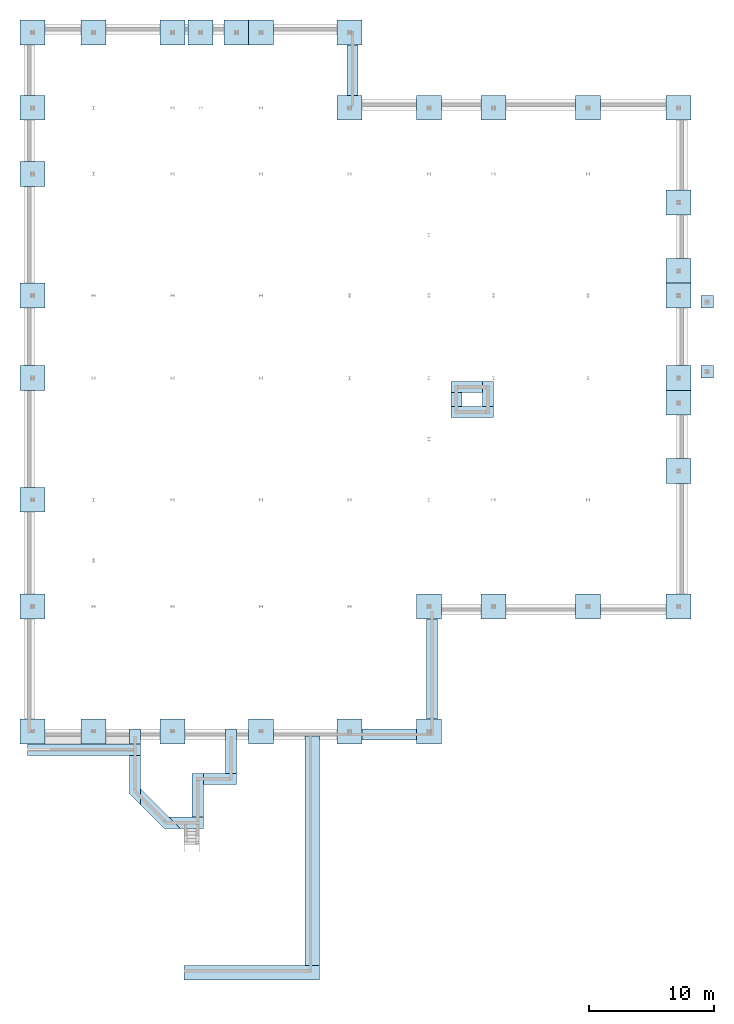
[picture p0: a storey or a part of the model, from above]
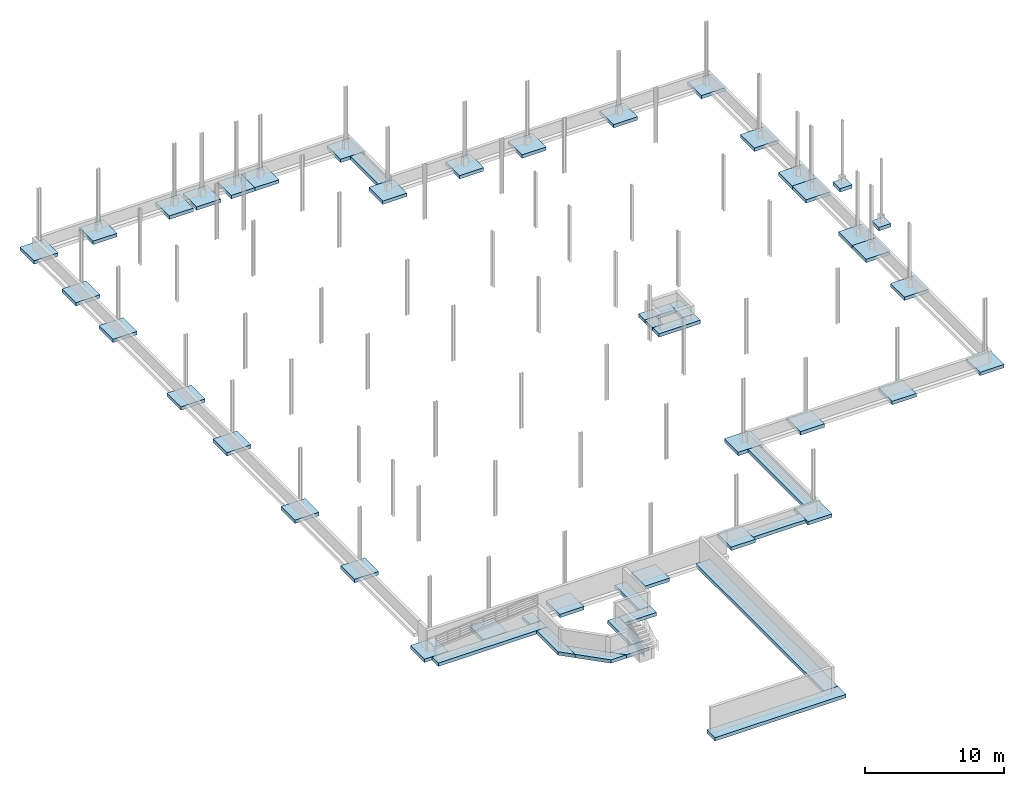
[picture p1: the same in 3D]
Properties of the parts of a building model (IFC2X3), part 1 of 3

# File
Description: ViewDefinition [CoordinationView]
File name: Project Number
Time: 2011-07-11T15:46:36
Written by: Autodesk Revit Architecture 2011 - 1.0
Made in: (Solibri IFC Optimizer)

# IfcProject, Project Number
Phase: Project Status

# IfcSite, Default
RefLatitude: 42, 21, 30, 344238; RefLongitude: -71, -3, -35, -194702; RefElevation: 0 m

# IfcBuilding
Pset_BuildingCommon - NumberOfStoreys: 4
PSet_Revit_Other - Project Issue Date: Issue Date; Project Status: Project Status; Client Name: Owner; Project Address: Enter address here; Project Name: Project Name; Project Number: Project Number; Category Description: OmniClass Table 11 Description; Category Code: OmniClass Table 11 Code

# IfcBuildingStorey (4)
PSet_Revit_Type_Graphics - Line Weight: 1; Color: 0; Line Pattern: Centre; Symbol: M_Level Head - Circle; Symbol at End 1 Default: no; Symbol at End 2 Default: yes
PSet_Revit_Type_Constraints - Elevation Base: 0
PSet_Revit_Type_Dimensions - Automatic Room Computation Height: yes
Name | Elevation (m) | Category Code | PSet_Revit_Constraints, Elevation (m) | Name
Roof - Main | 9.25 | Roof | 9.25 | Roof - Main
Second Floor | 4.57 | Floor | 4.57 | Second Floor
TOF Footing | -1 | Site | -1 | TOF Footing
First Floor | -3.5315e-13 | Floor | 0 | First Floor

# IfcBeam: M_K-Series Bar Joist-Rod Web:10K1:228953 (5)
In: First Floor
PSet_Revit_Structural Analysis - Start Release: 3; Start Fx: no; Start Fy: no; Start Fz: no; Start Mx: no; Start My: yes; Start Mz: yes; End Release: 1; End Fx: no; End Fy: no; End Fz: no; End Mx: yes; End My: yes; End Mz: yes; Analyze As: 1
PSet_Revit_Other - PanelArrayNum: 3; PanelArrayLength: 1.351 m; Panel: 0.450333 m; InstallationDate: InstallationDate; SerialNumber: SerialNumber; WarrantyStartDate: WarrantyStartDate; BarCode: BarCode; AssetIdentifier: AssetIdentifier; TagNumber: TagNumber
PSet_Revit_Analytical Model - Rigid Links: 0; Horizontal Projection: Default
PSet_Revit_Structural - Cut Length: 2.367 m; Structural Usage: 4
PSet_Revit_Construction - Start Offset: 0 m; Start Extension: 0 m; End Offset: 0 m; End Extension: 0 m
Pset_BeamCommon - Reference: M_K-Series Bar Joist-Rod Web:10K1; IsExternal: no; LoadBearing: yes; Span: 0.0095 m; Slope: 0 deg
PSet_Revit_Dimensions - Length: 2.367 m; Volume: 0.00307691 m3
PSet_Revit_Phasing - Phase Created: New Construction
PSet_Revit_Constraints - Work Plane: Level : Second Floor; Reference Level: Second Floor; Start Level Offset: 0 m; End Level Offset: 0 m; z-Direction Justification: 3; z-Direction Offset Value: -0.102 m; Lateral Justification: 0; Orientation: 0; Cross-Section Rotation: 0 deg
PSet_Revit_Type_Identity Data - Manufacturer: Manufacturer; OmniClass Number: 23.25.30.21.14.11; OmniClass Title: Metal Joists
PSet_Revit_Type_Dimensions - Web Thickness: 0.0095 m; Seat Length: 0.1 m; Seat Depth: 0.0635 m; Cord Leg: 0.032 m; Chord Thickness: 0.0065 m; Depth: 0.254 m
PSet_Revit_Type_Structural - M: 7.4
PSet_Revit_Type_Other - End Panel: 0.508 m; AccessibilityPerformance: AccessibilityPerformance; CodePerformance: CodePerformance; Color: Color; Constituents: Constituents; Features: Features; Finish: Finish; Grade: Grade; Material: Material; ModelReference: ModelReference; NominalHeight: NominalHeight; NominalLength: NominalLength; NominalWidth: NominalWidth; ProductionYear: ProductionYear; Reference: Reference; Shape: Shape; Size: Size; SustainabilityPerformance: SustainabilityPerformance; WarrantyDescription: WarrantyDescription; WarrantyDurationLabor: WarrantyDurationLabor; WarrantyDurationParts: WarrantyDurationParts; WarrantyGuarantorLabor: WarrantyGuarantorLabor; WarrantyGuarantorParts: WarrantyGuarantorParts; ExpectedLife: ExpectedLife; ReplacementCost: ReplacementCost; AssetAccountingType: FIXED; ModelLabel: ModelLabel
Name (M_K-Series Bar Joist-Rod Web:10K1:10K1:...)
228924
228926
228928
228920
228922

# IfcBeam: M_K-Series Bar Joist-Rod Web:14K1:175829 (456)
PSet_Revit_Constraints - Start Level Offset: 0 m; End Level Offset: 0 m; z-Direction Justification: 3; Lateral Justification: 0; Orientation: 0; Cross-Section Rotation: 0 deg
PSet_Revit_Structural Analysis - Start Release: 3; Start Fx: no; Start Fy: no; Start Fz: no; Start Mx: no; Start My: yes; Start Mz: yes; End Release: 1; End Fx: no; End Fy: no; End Fz: no; End Mx: yes; End My: yes; End Mz: yes; Analyze As: 1
PSet_Revit_Analytical Model - Rigid Links: 0; Horizontal Projection: Default
PSet_Revit_Structural - Structural Usage: 4
PSet_Revit_Construction - Start Offset: 0 m; Start Extension: 0 m; End Offset: 0 m; End Extension: 0 m
PSet_Revit_Phasing - Phase Created: New Construction
Pset_BeamCommon - Reference: M_K-Series Bar Joist-Rod Web:14K1; IsExternal: no; LoadBearing: yes; Span: 0.0095 m
PSet_Revit_Other - InstallationDate: InstallationDate; SerialNumber: SerialNumber; WarrantyStartDate: WarrantyStartDate; BarCode: BarCode; AssetIdentifier: AssetIdentifier; TagNumber: TagNumber
PSet_Revit_Type_Structural - M: 7.7
PSet_Revit_Type_Dimensions - Web Thickness: 0.0095 m; Seat Length: 0.1 m; Seat Depth: 0.0635 m; Cord Leg: 0.032 m; Chord Thickness: 0.0065 m; Depth: 0.356 m
PSet_Revit_Type_Identity Data - Manufacturer: Manufacturer; OmniClass Number: 23.25.30.21.14.11; OmniClass Title: Metal Joists
PSet_Revit_Type_Other - End Panel: 0.712 m; AccessibilityPerformance: AccessibilityPerformance; CodePerformance: CodePerformance; Color: Color; Constituents: Constituents; Features: Features; Finish: Finish; Grade: Grade; Material: Material; ModelReference: ModelReference; NominalHeight: NominalHeight; NominalLength: NominalLength; NominalWidth: NominalWidth; ProductionYear: ProductionYear; Reference: Reference; Shape: Shape; Size: Size; SustainabilityPerformance: SustainabilityPerformance; WarrantyDescription: WarrantyDescription; WarrantyDurationLabor: WarrantyDurationLabor; WarrantyDurationParts: WarrantyDurationParts; WarrantyGuarantorLabor: WarrantyGuarantorLabor; WarrantyGuarantorParts: WarrantyGuarantorParts; ExpectedLife: ExpectedLife; ReplacementCost: ReplacementCost; AssetAccountingType: FIXED; ModelLabel: ModelLabel
Name (M_K-Series Bar Joist-Rod Web:14K1:14K1:...) | In | Work Plane | Reference Level | z-Direction Offset Value (m) | Cut Length (m) = Length (m) | Slope (deg) | PanelArrayNum | PanelArrayLength (m) | Panel (m) | Volume (m3)
220116 | Second Floor | Level : Roof - Main | Roof - Main | 0 | 8.969 | 0 | 11 | 7.545 | 0.685909 | 0.0126419
220117 | Second Floor | Level : Roof - Main | Roof - Main | 0 | 8.969 | 0 | 11 | 7.545 | 0.685909 | 0.0126419
225612 | First Floor | Level : Second Floor | Second Floor | -0.102 | 5.309 | 0 | 5 | 3.885 | 0.777 | 0.00717022
220100 | Second Floor | Level : Roof - Main | Roof - Main | 0 | 8.975 | 0 | 11 | 7.551 | 0.686455 | 0.0126509
220081 | Second Floor | Level : Roof - Main | Roof - Main | 0 | 8.975 | 1.30141e-30 | 11 | 7.551 | 0.686455 | 0.0126509
189399 | Second Floor | Level : Roof - Main | Roof - Main | 0 | 8.57 | 0 | 10 | 7.146 | 0.7146 | 0.0120454
225467 | First Floor | Level : Second Floor | Second Floor | -0.102 | 8.57 | 0 | 10 | 7.146 | 0.7146 | 0.0120454
189397 | Second Floor | Level : Roof - Main | Roof - Main | 0 | 8.57 | 0 | 10 | 7.146 | 0.7146 | 0.0120454
225611 | First Floor | Level : Second Floor | Second Floor | -0.102 | 5.309 | 0 | 5 | 3.885 | 0.777 | 0.00717022
185401 | First Floor | Level : Second Floor | Second Floor | -0.102 | 6.629 | 0 | 7 | 5.205 | 0.743571 | 0.00914362
185451 | First Floor | Level : Second Floor | Second Floor | -0.102 | 8.57 | 0 | 10 | 7.146 | 0.7146 | 0.0120454
220080 | Second Floor | Level : Roof - Main | Roof - Main | 0 | 8.975 | 1.30141e-30 | 11 | 7.551 | 0.686455 | 0.0126509
185266 | First Floor | Level : Second Floor | Second Floor | -0.102 | 6.05 | 0 | 6 | 4.626 | 0.771 | 0.00827801
185267 | First Floor | Level : Second Floor | Second Floor | -0.102 | 6.05 | 0 | 6 | 4.626 | 0.771 | 0.00827801
220027 | Second Floor | Level : Roof - Main | Roof - Main | 0 | 8.975 | 1.30141e-30 | 11 | 7.551 | 0.686455 | 0.0126509
189395 | Second Floor | Level : Roof - Main | Roof - Main | 0 | 8.57 | 0 | 10 | 7.146 | 0.7146 | 0.0120454
220118 | Second Floor | Level : Roof - Main | Roof - Main | 0 | 8.969 | 0 | 11 | 7.545 | 0.685909 | 0.0126419
189398 | Second Floor | Level : Roof - Main | Roof - Main | 0 | 8.57 | 0 | 10 | 7.146 | 0.7146 | 0.0120454
189623 | Second Floor | Level : Roof - Main | Roof - Main | 0 | 5.309 | 2.01996e-30 | 5 | 3.885 | 0.777 | 0.00717022
185555 | First Floor | Level : Second Floor | Second Floor | -0.102 | 8.57 | 0 | 10 | 7.146 | 0.7146 | 0.0120454
189620 | Second Floor | Level : Roof - Main | Roof - Main | 0 | 5.309 | 2.01996e-30 | 5 | 3.885 | 0.777 | 0.00717022
190259 | Second Floor | Level : Roof - Main | Roof - Main | 0 | 8.57 | 1.97385e-30 | 10 | 7.146 | 0.7146 | 0.0120454
220061 | Second Floor | Level : Roof - Main | Roof - Main | 0 | 8.975 | 0 | 11 | 7.551 | 0.686455 | 0.0126509
220060 | Second Floor | Level : Roof - Main | Roof - Main | 0 | 8.975 | 0 | 11 | 7.551 | 0.686455 | 0.0126509
225615 | First Floor | Level : Second Floor | Second Floor | -0.102 | 5.309 | 0 | 5 | 3.885 | 0.777 | 0.00717022
185400 | First Floor | Level : Second Floor | Second Floor | -0.102 | 6.629 | 0 | 7 | 5.205 | 0.743571 | 0.00914362
185287 | First Floor | Level : Second Floor | Second Floor | -0.102 | 9.77 | 0 | 12 | 8.346 | 0.6955 | 0.0138394
185450 | First Floor | Level : Second Floor | Second Floor | -0.102 | 8.57 | 0 | 10 | 7.146 | 0.7146 | 0.0120454
189973 | Second Floor | Level : Roof - Main | Roof - Main | 0 | 8.57 | 0 | 10 | 7.146 | 0.7146 | 0.0120454
220097 | Second Floor | Level : Roof - Main | Roof - Main | 0 | 8.975 | 0 | 11 | 7.551 | 0.686455 | 0.0126509
185556 | First Floor | Level : Second Floor | Second Floor | -0.102 | 8.57 | 0 | 10 | 7.146 | 0.7146 | 0.0120454
185269 | First Floor | Level : Second Floor | Second Floor | -0.102 | 6.05 | 0 | 6 | 4.626 | 0.771 | 0.00827801
185362 | First Floor | Level : Second Floor | Second Floor | -0.102 | 5.309 | 0 | 5 | 3.885 | 0.777 | 0.00717022
185557 | First Floor | Level : Second Floor | Second Floor | -0.102 | 8.57 | 0 | 10 | 7.146 | 0.7146 | 0.0120454
190260 | Second Floor | Level : Roof - Main | Roof - Main | 0 | 8.57 | 1.97385e-30 | 10 | 7.146 | 0.7146 | 0.0120454
185553 | First Floor | Level : Second Floor | Second Floor | -0.102 | 8.57 | 0 | 10 | 7.146 | 0.7146 | 0.0120454
231532 | Second Floor | Level : Roof - Main | Roof - Main | 0 | 8.975 | 0 | 11 | 7.551 | 0.686455 | 0.0126509
185558 | First Floor | Level : Second Floor | Second Floor | -0.102 | 8.57 | 0 | 10 | 7.146 | 0.7146 | 0.0120454
189657 | Second Floor | Level : Roof - Main | Roof - Main | 0 | 9.769 | 9.79552e-31 | 12 | 8.345 | 0.695417 | 0.0138379
220062 | Second Floor | Level : Roof - Main | Roof - Main | 0 | 8.975 | 0 | 11 | 7.551 | 0.686455 | 0.0126509
225471 | First Floor | Level : Second Floor | Second Floor | -0.102 | 8.57 | 0 | 10 | 7.146 | 0.7146 | 0.0120454
190262 | Second Floor | Level : Roof - Main | Roof - Main | 0 | 8.57 | 1.97385e-30 | 10 | 7.146 | 0.7146 | 0.0120454
185740 | First Floor | Level : Second Floor | Second Floor | -0.102 | 10.039 | 0 | 12 | 8.615 | 0.717917 | 0.0142416
185286 | First Floor | Level : Second Floor | Second Floor | -0.102 | 9.77 | 0 | 12 | 8.346 | 0.6955 | 0.0138394
185268 | First Floor | Level : Second Floor | Second Floor | -0.102 | 6.05 | 0 | 6 | 4.626 | 0.771 | 0.00827801
225613 | First Floor | Level : Second Floor | Second Floor | -0.102 | 5.309 | 0 | 5 | 3.885 | 0.777 | 0.00717022
220112 | Second Floor | Level : Roof - Main | Roof - Main | 0 | 8.969 | 0 | 11 | 7.545 | 0.685909 | 0.0126419
189396 | Second Floor | Level : Roof - Main | Roof - Main | 0 | 8.57 | 0 | 10 | 7.146 | 0.7146 | 0.0120454
225473 | First Floor | Level : Second Floor | Second Floor | -0.102 | 8.57 | 0 | 10 | 7.146 | 0.7146 | 0.0120454
189434 | Second Floor | Level : Roof - Main | Roof - Main | 0 | 8.57 | 0 | 10 | 7.146 | 0.7146 | 0.0120454
189433 | Second Floor | Level : Roof - Main | Roof - Main | 0 | 8.57 | 0 | 10 | 7.146 | 0.7146 | 0.0120454
189725 | Second Floor | Level : Roof - Main | Roof - Main | 0 | 5.309 | 2.01996e-30 | 5 | 3.885 | 0.777 | 0.00717022
190338 | Second Floor | Level : Roof - Main | Roof - Main | 0 | 5.31 | 1.01005e-30 | 5 | 3.886 | 0.7772 | 0.00717171
220098 | Second Floor | Level : Roof - Main | Roof - Main | 0 | 8.975 | 0 | 11 | 7.551 | 0.686455 | 0.0126509
189970 | Second Floor | Level : Roof - Main | Roof - Main | 0 | 8.57 | 0 | 10 | 7.146 | 0.7146 | 0.0120454
231536 | Second Floor | Level : Roof - Main | Roof - Main | 0 | 8.975 | 0 | 11 | 7.551 | 0.686455 | 0.0126509
185492 | First Floor | Level : Second Floor | Second Floor | -0.102 | 10.039 | 0 | 12 | 8.615 | 0.717917 | 0.0142416
189464 | Second Floor | Level : Roof - Main | Roof - Main | 0 | 8.57 | 0 | 10 | 7.146 | 0.7146 | 0.0120454
220101 | Second Floor | Level : Roof - Main | Roof - Main | 0 | 8.975 | 0 | 11 | 7.551 | 0.686455 | 0.0126509
220114 | Second Floor | Level : Roof - Main | Roof - Main | 0 | 8.969 | 0 | 11 | 7.545 | 0.685909 | 0.0126419
189400 | Second Floor | Level : Roof - Main | Roof - Main | 0 | 8.57 | 0 | 10 | 7.146 | 0.7146 | 0.0120454
225616 | First Floor | Level : Second Floor | Second Floor | -0.102 | 5.309 | 0 | 5 | 3.885 | 0.777 | 0.00717022
220063 | Second Floor | Level : Roof - Main | Roof - Main | 0 | 8.975 | 0 | 11 | 7.551 | 0.686455 | 0.0126509
189411 | Second Floor | Level : Roof - Main | Roof - Main | 0 | 8.57 | 1.97385e-30 | 10 | 7.146 | 0.7146 | 0.0120454
189429 | Second Floor | Level : Roof - Main | Roof - Main | 0 | 8.57 | 0 | 10 | 7.146 | 0.7146 | 0.0120454
189968 | Second Floor | Level : Roof - Main | Roof - Main | 0 | 8.57 | 0 | 10 | 7.146 | 0.7146 | 0.0120454
220113 | Second Floor | Level : Roof - Main | Roof - Main | 0 | 8.969 | 0 | 11 | 7.545 | 0.685909 | 0.0126419
185399 | First Floor | Level : Second Floor | Second Floor | -0.102 | 6.629 | 0 | 7 | 5.205 | 0.743571 | 0.00914362
185437 | First Floor | Level : Second Floor | Second Floor | -0.102 | 9.77 | 0 | 12 | 8.346 | 0.6955 | 0.0138394
220045 | Second Floor | Level : Roof - Main | Roof - Main | 0 | 8.975 | 1.30141e-30 | 11 | 7.551 | 0.686455 | 0.0126509
189608 | Second Floor | Level : Roof - Main | Roof - Main | 0 | 5.309 | 0 | 5 | 3.885 | 0.777 | 0.00717022
185772 | First Floor | Level : Second Floor | Second Floor | -0.102 | 10.039 | 0 | 12 | 8.615 | 0.717917 | 0.0142416
189413 | Second Floor | Level : Roof - Main | Roof - Main | 0 | 8.57 | 1.97385e-30 | 10 | 7.146 | 0.7146 | 0.0120454
186278 | First Floor | Level : Second Floor | Second Floor | -0.102 | 6.629 | 0 | 7 | 5.205 | 0.743571 | 0.00914362
231535 | Second Floor | Level : Roof - Main | Roof - Main | 0 | 8.975 | 0 | 11 | 7.551 | 0.686455 | 0.0126509
185773 | First Floor | Level : Second Floor | Second Floor | -0.102 | 10.039 | 0 | 12 | 8.615 | 0.717917 | 0.0142416
189637 | Second Floor | Level : Roof - Main | Roof - Main | 0 | 5.309 | 0 | 5 | 3.885 | 0.777 | 0.00717022
220083 | Second Floor | Level : Roof - Main | Roof - Main | 0 | 8.975 | 1.30141e-30 | 11 | 7.551 | 0.686455 | 0.0126509
190339 | Second Floor | Level : Roof - Main | Roof - Main | 0 | 5.309 | 2.01996e-30 | 5 | 3.885 | 0.777 | 0.00717022
220025 | Second Floor | Level : Roof - Main | Roof - Main | 0 | 8.975 | 1.30141e-30 | 11 | 7.551 | 0.686455 | 0.0126509
220082 | Second Floor | Level : Roof - Main | Roof - Main | 0 | 8.975 | 1.30141e-30 | 11 | 7.551 | 0.686455 | 0.0126509
186277 | First Floor | Level : Second Floor | Second Floor | -0.102 | 6.629 | 0 | 7 | 5.205 | 0.743571 | 0.00914362
185538 | First Floor | Level : Second Floor | Second Floor | -0.102 | 10.039 | 0 | 12 | 8.615 | 0.717917 | 0.0142416
185491 | First Floor | Level : Second Floor | Second Floor | -0.102 | 10.039 | 0 | 12 | 8.615 | 0.717917 | 0.0142416
189853 | Second Floor | Level : Roof - Main | Roof - Main | 0 | 6.05 | 0 | 6 | 4.626 | 0.771 | 0.00827801
220028 | Second Floor | Level : Roof - Main | Roof - Main | 0 | 8.975 | 1.30141e-30 | 11 | 7.551 | 0.686455 | 0.0126509
189727 | Second Floor | Level : Roof - Main | Roof - Main | 0 | 5.309 | 2.01996e-30 | 5 | 3.885 | 0.777 | 0.00717022
220023 | Second Floor | Level : Roof - Main | Roof - Main | 0 | 8.975 | 1.30141e-30 | 11 | 7.551 | 0.686455 | 0.0126509
189707 | Second Floor | Level : Roof - Main | Roof - Main | 0 | 9.769 | 9.79552e-31 | 12 | 8.345 | 0.695417 | 0.0138379
185453 | First Floor | Level : Second Floor | Second Floor | -0.102 | 8.57 | 0 | 10 | 7.146 | 0.7146 | 0.0120454
185435 | First Floor | Level : Second Floor | Second Floor | -0.102 | 9.77 | 0 | 12 | 8.346 | 0.6955 | 0.0138394
225472 | First Floor | Level : Second Floor | Second Floor | -0.102 | 8.57 | 0 | 10 | 7.146 | 0.7146 | 0.0120454
225468 | First Floor | Level : Second Floor | Second Floor | -0.102 | 8.57 | 0 | 10 | 7.146 | 0.7146 | 0.0120454
185739 | First Floor | Level : Second Floor | Second Floor | -0.102 | 10.039 | 0 | 12 | 8.615 | 0.717917 | 0.0142416
190263 | Second Floor | Level : Roof - Main | Roof - Main | 0 | 8.57 | 1.97385e-30 | 10 | 7.146 | 0.7146 | 0.0120454
220099 | Second Floor | Level : Roof - Main | Roof - Main | 0 | 8.975 | 0 | 11 | 7.551 | 0.686455 | 0.0126509
231531 | Second Floor | Level : Roof - Main | Roof - Main | 0 | 8.975 | 0 | 11 | 7.551 | 0.686455 | 0.0126509
189622 | Second Floor | Level : Roof - Main | Roof - Main | 0 | 5.309 | 2.01996e-30 | 5 | 3.885 | 0.777 | 0.00717022
220022 | Second Floor | Level : Roof - Main | Roof - Main | 0 | 8.975 | 1.30141e-30 | 11 | 7.551 | 0.686455 | 0.0126509
186279 | First Floor | Level : Second Floor | Second Floor | -0.102 | 6.629 | 0 | 7 | 5.205 | 0.743571 | 0.00914362
225614 | First Floor | Level : Second Floor | Second Floor | -0.102 | 5.309 | 0 | 5 | 3.885 | 0.777 | 0.00717022
185534 | First Floor | Level : Second Floor | Second Floor | -0.102 | 10.039 | 0 | 12 | 8.615 | 0.717917 | 0.0142416
190336 | Second Floor | Level : Roof - Main | Roof - Main | 0 | 5.309 | 2.01996e-30 | 5 | 3.885 | 0.777 | 0.00717022
220043 | Second Floor | Level : Roof - Main | Roof - Main | 0 | 8.975 | 1.30141e-30 | 11 | 7.551 | 0.686455 | 0.0126509
220026 | Second Floor | Level : Roof - Main | Roof - Main | 0 | 8.975 | 1.30141e-30 | 11 | 7.551 | 0.686455 | 0.0126509
231533 | Second Floor | Level : Roof - Main | Roof - Main | 0 | 8.975 | 0 | 11 | 7.551 | 0.686455 | 0.0126509
188687 | First Floor | Level : Second Floor | Second Floor | -0.102 | 6.935 | 0 | 8 | 5.511 | 0.688875 | 0.00960109
220049 | Second Floor | Level : Roof - Main | Roof - Main | 0 | 8.975 | 1.30141e-30 | 11 | 7.551 | 0.686455 | 0.0126509
189415 | Second Floor | Level : Roof - Main | Roof - Main | 0 | 8.57 | 1.97385e-30 | 10 | 7.146 | 0.7146 | 0.0120454
185554 | First Floor | Level : Second Floor | Second Floor | -0.102 | 8.57 | 0 | 10 | 7.146 | 0.7146 | 0.0120454
186266 | First Floor | Level : Second Floor | Second Floor | -0.102 | 9.77 | 6.53056e-31 | 12 | 8.346 | 0.6955 | 0.0138394
220007 | Second Floor | Level : Roof - Main | Roof - Main | 0 | 8.975 | 0 | 11 | 7.551 | 0.686455 | 0.0126509
189331 | Second Floor | Level : Roof - Main | Roof - Main | 0 | 9.77 | 0 | 12 | 8.346 | 0.6955 | 0.0138394
189955 | Second Floor | Level : Roof - Main | Roof - Main | 0 | 8.57 | 1.97385e-30 | 10 | 7.146 | 0.7146 | 0.0120454
189969 | Second Floor | Level : Roof - Main | Roof - Main | 0 | 8.57 | 0 | 10 | 7.146 | 0.7146 | 0.0120454
185285 | First Floor | Level : Second Floor | Second Floor | -0.102 | 9.77 | 0 | 12 | 8.346 | 0.6955 | 0.0138394
189619 | Second Floor | Level : Roof - Main | Roof - Main | 0 | 5.309 | 2.01996e-30 | 5 | 3.885 | 0.777 | 0.00717022
220065 | Second Floor | Level : Roof - Main | Roof - Main | 0 | 8.975 | 0 | 11 | 7.551 | 0.686455 | 0.0126509
189956 | Second Floor | Level : Roof - Main | Roof - Main | 0 | 8.57 | 1.97385e-30 | 10 | 7.146 | 0.7146 | 0.0120454
185736 | First Floor | Level : Second Floor | Second Floor | -0.102 | 10.039 | 0 | 12 | 8.615 | 0.717917 | 0.0142416
225617 | First Floor | Level : Second Floor | Second Floor | -0.102 | 5.309 | 0 | 5 | 3.885 | 0.777 | 0.00717022
189462 | Second Floor | Level : Roof - Main | Roof - Main | 0 | 8.57 | 0 | 10 | 7.146 | 0.7146 | 0.0120454
185738 | First Floor | Level : Second Floor | Second Floor | -0.102 | 10.039 | 0 | 12 | 8.615 | 0.717917 | 0.0142416
189636 | Second Floor | Level : Roof - Main | Roof - Main | 0 | 5.309 | 0 | 5 | 3.885 | 0.777 | 0.00717022
185398 | First Floor | Level : Second Floor | Second Floor | -0.102 | 6.629 | 0 | 7 | 5.205 | 0.743571 | 0.00914362
189414 | Second Floor | Level : Roof - Main | Roof - Main | 0 | 8.57 | 1.97385e-30 | 10 | 7.146 | 0.7146 | 0.0120454
185769 | First Floor | Level : Second Floor | Second Floor | -0.102 | 10.039 | 0 | 12 | 8.615 | 0.717917 | 0.0142416
189671 | Second Floor | Level : Roof - Main | Roof - Main | 0 | 6.629 | 0 | 7 | 5.205 | 0.743571 | 0.00914362
225470 | First Floor | Level : Second Floor | Second Floor | -0.102 | 8.57 | 0 | 10 | 7.146 | 0.7146 | 0.0120454
186263 | First Floor | Level : Second Floor | Second Floor | -0.102 | 9.77 | 6.53056e-31 | 12 | 8.346 | 0.6955 | 0.0138394
189670 | Second Floor | Level : Roof - Main | Roof - Main | 0 | 6.629 | 0 | 7 | 5.205 | 0.743571 | 0.00914362
188689 | First Floor | Level : Second Floor | Second Floor | -0.102 | 6.935 | 0 | 8 | 5.511 | 0.688875 | 0.00960109
189639 | Second Floor | Level : Roof - Main | Roof - Main | 0 | 5.309 | 0 | 5 | 3.885 | 0.777 | 0.00717022
189972 | Second Floor | Level : Roof - Main | Roof - Main | 0 | 8.57 | 0 | 10 | 7.146 | 0.7146 | 0.0120454
189669 | Second Floor | Level : Roof - Main | Roof - Main | 0 | 6.629 | 0 | 7 | 5.205 | 0.743571 | 0.00914362
185288 | First Floor | Level : Second Floor | Second Floor | -0.102 | 9.77 | 0 | 12 | 8.346 | 0.6955 | 0.0138394
190337 | Second Floor | Level : Roof - Main | Roof - Main | 0 | 5.309 | 2.01996e-30 | 5 | 3.885 | 0.777 | 0.00717022
185668 | First Floor | Level : Second Floor | Second Floor | -0.102 | 8.57 | 0 | 10 | 7.146 | 0.7146 | 0.0120454
220024 | Second Floor | Level : Roof - Main | Roof - Main | 0 | 8.975 | 1.30141e-30 | 11 | 7.551 | 0.686455 | 0.0126509
189705 | Second Floor | Level : Roof - Main | Roof - Main | 0 | 9.769 | 9.79552e-31 | 12 | 8.345 | 0.695417 | 0.0138379
185774 | First Floor | Level : Second Floor | Second Floor | -0.102 | 10.039 | 0 | 12 | 8.615 | 0.717917 | 0.0142416
185490 | First Floor | Level : Second Floor | Second Floor | -0.102 | 10.039 | 0 | 12 | 8.615 | 0.717917 | 0.0142416
189640 | Second Floor | Level : Roof - Main | Roof - Main | 0 | 5.309 | 0 | 5 | 3.885 | 0.777 | 0.00717022
189854 | Second Floor | Level : Roof - Main | Roof - Main | 0 | 6.05 | 0 | 6 | 4.626 | 0.771 | 0.00827801
188688 | First Floor | Level : Second Floor | Second Floor | -0.102 | 6.935 | 0 | 8 | 5.511 | 0.688875 | 0.00960109
190261 | Second Floor | Level : Roof - Main | Roof - Main | 0 | 8.57 | 1.97385e-30 | 10 | 7.146 | 0.7146 | 0.0120454
185824 | First Floor | Level : Second Floor | Second Floor | -0.102 | 9.77 | 0 | 12 | 8.346 | 0.6955 | 0.0138394
231534 | Second Floor | Level : Roof - Main | Roof - Main | 0 | 8.975 | 0 | 11 | 7.551 | 0.686455 | 0.0126509
185735 | First Floor | Level : Second Floor | Second Floor | -0.102 | 10.039 | 0 | 12 | 8.615 | 0.717917 | 0.0142416
220047 | Second Floor | Level : Roof - Main | Roof - Main | 0 | 8.975 | 1.30141e-30 | 11 | 7.551 | 0.686455 | 0.0126509
185434 | First Floor | Level : Second Floor | Second Floor | -0.102 | 9.77 | 0 | 12 | 8.346 | 0.6955 | 0.0138394
185669 | First Floor | Level : Second Floor | Second Floor | -0.102 | 8.57 | 0 | 10 | 7.146 | 0.7146 | 0.0120454
189635 | Second Floor | Level : Roof - Main | Roof - Main | 0 | 5.309 | 0 | 5 | 3.885 | 0.777 | 0.00717022
220096 | Second Floor | Level : Roof - Main | Roof - Main | 0 | 8.975 | 0 | 11 | 7.551 | 0.686455 | 0.0126509
189668 | Second Floor | Level : Roof - Main | Roof - Main | 0 | 6.629 | 0 | 7 | 5.205 | 0.743571 | 0.00914362
220001 | Second Floor | Level : Roof - Main | Roof - Main | 0 | 8.975 | 0 | 11 | 7.551 | 0.686455 | 0.0126509
189306 | Second Floor | Level : Roof - Main | Roof - Main | 0 | 5.309 | 0 | 5 | 3.885 | 0.777 | 0.00717022
189431 | Second Floor | Level : Roof - Main | Roof - Main | 0 | 8.57 | 0 | 10 | 7.146 | 0.7146 | 0.0120454
188686 | First Floor | Level : Second Floor | Second Floor | -0.102 | 6.935 | 0 | 8 | 5.511 | 0.688875 | 0.00960109
189412 | Second Floor | Level : Roof - Main | Roof - Main | 0 | 8.57 | 1.97385e-30 | 10 | 7.146 | 0.7146 | 0.0120454
189724 | Second Floor | Level : Roof - Main | Roof - Main | 0 | 5.309 | 2.01996e-30 | 5 | 3.885 | 0.777 | 0.00717022
185539 | First Floor | Level : Second Floor | Second Floor | -0.102 | 10.039 | 0 | 12 | 8.615 | 0.717917 | 0.0142416
220066 | Second Floor | Level : Roof - Main | Roof - Main | 0 | 8.975 | 0 | 11 | 7.551 | 0.686455 | 0.0126509
189654 | Second Floor | Level : Roof - Main | Roof - Main | 0 | 9.769 | 9.79552e-31 | 12 | 8.345 | 0.695417 | 0.0138379
186281 | First Floor | Level : Second Floor | Second Floor | -0.102 | 6.629 | 0 | 7 | 5.205 | 0.743571 | 0.00914362
185752 | First Floor | Level : Second Floor | Second Floor | -0.102 | 10.039 | 0 | 12 | 8.615 | 0.717917 | 0.0142416
185756 | First Floor | Level : Second Floor | Second Floor | -0.102 | 10.039 | 0 | 12 | 8.615 | 0.717917 | 0.0142416
185632 | First Floor | Level : Second Floor | Second Floor | -0.102 | 9.77 | 0 | 12 | 8.346 | 0.6955 | 0.0138394
189428 | Second Floor | Level : Roof - Main | Roof - Main | 0 | 8.57 | 0 | 10 | 7.146 | 0.7146 | 0.0120454
219950 | Second Floor | Level : Roof - Main | Roof - Main | 0 | 8.975 | 0 | 11 | 7.551 | 0.686455 | 0.0126509
225469 | First Floor | Level : Second Floor | Second Floor | -0.102 | 8.57 | 0 | 10 | 7.146 | 0.7146 | 0.0120454
219990 | Second Floor | Level : Roof - Main | Roof - Main | 0 | 8.975 | 1.30141e-30 | 11 | 7.551 | 0.686455 | 0.0126509
189706 | Second Floor | Level : Roof - Main | Roof - Main | 0 | 9.769 | 9.79552e-31 | 12 | 8.345 | 0.695417 | 0.0138379
188723 | First Floor | Level : Second Floor | Second Floor | -0.102 | 2.834 | 0 | 2 | 1.41 | 0.705 | 0.00347009
185631 | First Floor | Level : Second Floor | Second Floor | -0.102 | 9.77 | 0 | 12 | 8.346 | 0.6955 | 0.0138394
185537 | First Floor | Level : Second Floor | Second Floor | -0.102 | 10.039 | 0 | 12 | 8.615 | 0.717917 | 0.0142416
189465 | Second Floor | Level : Roof - Main | Roof - Main | 0 | 8.57 | 0 | 10 | 7.146 | 0.7146 | 0.0120454
185535 | First Floor | Level : Second Floor | Second Floor | -0.102 | 10.039 | 0 | 12 | 8.615 | 0.717917 | 0.0142416
186299 | First Floor | Level : Second Floor | Second Floor | -0.102 | 9.77 | 0 | 12 | 8.346 | 0.6955 | 0.0138394
189730 | Second Floor | Level : Roof - Main | Roof - Main | 0 | 5.309 | 2.01996e-30 | 5 | 3.885 | 0.777 | 0.00717022
190335 | Second Floor | Level : Roof - Main | Roof - Main | 0 | 5.309 | 2.01996e-30 | 5 | 3.885 | 0.777 | 0.00717022
190341 | Second Floor | Level : Roof - Main | Roof - Main | 0 | 5.309 | 2.01996e-30 | 5 | 3.885 | 0.777 | 0.00717022
185617 | First Floor | Level : Second Floor | Second Floor | -0.102 | 6.05 | 0 | 6 | 4.626 | 0.771 | 0.00827801
189430 | Second Floor | Level : Roof - Main | Roof - Main | 0 | 8.57 | 0 | 10 | 7.146 | 0.7146 | 0.0120454
189417 | Second Floor | Level : Roof - Main | Roof - Main | 0 | 8.57 | 1.97385e-30 | 10 | 7.146 | 0.7146 | 0.0120454
189702 | Second Floor | Level : Roof - Main | Roof - Main | 0 | 9.769 | 9.79552e-31 | 12 | 8.345 | 0.695417 | 0.0138379
189621 | Second Floor | Level : Roof - Main | Roof - Main | 0 | 5.309 | 2.01996e-30 | 5 | 3.885 | 0.777 | 0.00717022
220079 | Second Floor | Level : Roof - Main | Roof - Main | 0 | 8.975 | 1.30141e-30 | 11 | 7.551 | 0.686455 | 0.0126509
189335 | Second Floor | Level : Roof - Main | Roof - Main | 0 | 9.769 | 0 | 12 | 8.345 | 0.695417 | 0.0138379
189652 | Second Floor | Level : Roof - Main | Roof - Main | 0 | 9.77 | 6.53056e-31 | 12 | 8.346 | 0.6955 | 0.0138394
188772 | First Floor | Level : Second Floor | Second Floor | -0.102 | 5.697 | 1.31467e-30 | 6 | 4.273 | 0.712167 | 0.00775028
185718 | First Floor | Level : Second Floor | Second Floor | -0.102 | 9.77 | 0 | 12 | 8.346 | 0.6955 | 0.0138394
190340 | Second Floor | Level : Roof - Main | Roof - Main | 0 | 5.309 | 2.01996e-30 | 5 | 3.885 | 0.777 | 0.00717022
189726 | Second Floor | Level : Roof - Main | Roof - Main | 0 | 5.309 | 2.01996e-30 | 5 | 3.885 | 0.777 | 0.00717022
185363 | First Floor | Level : Second Floor | Second Floor | -0.102 | 5.309 | 0 | 5 | 3.885 | 0.777 | 0.00717022
189690 | Second Floor | Level : Roof - Main | Roof - Main | 0 | 9.769 | 9.79552e-31 | 12 | 8.345 | 0.695417 | 0.0138379
185823 | First Floor | Level : Second Floor | Second Floor | -0.102 | 9.77 | 0 | 12 | 8.346 | 0.6955 | 0.0138394
189691 | Second Floor | Level : Roof - Main | Roof - Main | 0 | 9.769 | 9.79552e-31 | 12 | 8.345 | 0.695417 | 0.0138379
220115 | Second Floor | Level : Roof - Main | Roof - Main | 0 | 8.969 | 0 | 11 | 7.545 | 0.685909 | 0.0126419
189416 | Second Floor | Level : Roof - Main | Roof - Main | 0 | 8.57 | 1.97385e-30 | 10 | 7.146 | 0.7146 | 0.0120454
189586 | Second Floor | Level : Roof - Main | Roof - Main | 0 | 5.309 | 0 | 5 | 3.885 | 0.777 | 0.00717022
189463 | Second Floor | Level : Roof - Main | Roof - Main | 0 | 8.57 | 0 | 10 | 7.146 | 0.7146 | 0.0120454
189634 | Second Floor | Level : Roof - Main | Roof - Main | 0 | 5.309 | 0 | 5 | 3.885 | 0.777 | 0.00717022
186265 | First Floor | Level : Second Floor | Second Floor | -0.102 | 9.77 | 6.53056e-31 | 12 | 8.346 | 0.6955 | 0.0138394
189953 | Second Floor | Level : Roof - Main | Roof - Main | 0 | 8.57 | 1.97385e-30 | 10 | 7.146 | 0.7146 | 0.0120454
219946 | Second Floor | Level : Roof - Main | Roof - Main | 0 | 8.975 | 0 | 11 | 7.551 | 0.686455 | 0.0126509
189590 | Second Floor | Level : Roof - Main | Roof - Main | 0 | 5.309 | 0 | 5 | 3.885 | 0.777 | 0.00717022
220064 | Second Floor | Level : Roof - Main | Roof - Main | 0 | 8.975 | 0 | 11 | 7.551 | 0.686455 | 0.0126509
186298 | First Floor | Level : Second Floor | Second Floor | -0.102 | 9.77 | 0 | 12 | 8.346 | 0.6955 | 0.0138394
188690 | First Floor | Level : Second Floor | Second Floor | -0.102 | 6.935 | 0 | 8 | 5.511 | 0.688875 | 0.00960109
188758 | First Floor | Level : Second Floor | Second Floor | -0.102 | 8.57 | 0 | 10 | 7.146 | 0.7146 | 0.0120454
220006 | Second Floor | Level : Roof - Main | Roof - Main | 0 | 8.975 | 0 | 11 | 7.551 | 0.686455 | 0.0126509
189967 | Second Floor | Level : Roof - Main | Roof - Main | 0 | 8.57 | 0 | 10 | 7.146 | 0.7146 | 0.0120454
190265 | Second Floor | Level : Roof - Main | Roof - Main | 0 | 8.57 | 1.97385e-30 | 10 | 7.146 | 0.7146 | 0.0120454
185436 | First Floor | Level : Second Floor | Second Floor | -0.102 | 9.77 | 0 | 12 | 8.346 | 0.6955 | 0.0138394
189651 | Second Floor | Level : Roof - Main | Roof - Main | 0 | 9.77 | 6.53056e-31 | 12 | 8.346 | 0.6955 | 0.0138394
185722 | First Floor | Level : Second Floor | Second Floor | -0.102 | 9.77 | 0 | 12 | 8.346 | 0.6955 | 0.0138394
189606 | Second Floor | Level : Roof - Main | Roof - Main | 0 | 5.309 | 0 | 5 | 3.885 | 0.777 | 0.00717022
219988 | Second Floor | Level : Roof - Main | Roof - Main | 0 | 8.975 | 1.30141e-30 | 11 | 7.551 | 0.686455 | 0.0126509
220044 | Second Floor | Level : Roof - Main | Roof - Main | 0 | 8.975 | 1.30141e-30 | 11 | 7.551 | 0.686455 | 0.0126509
185719 | First Floor | Level : Second Floor | Second Floor | -0.102 | 9.77 | 0 | 12 | 8.346 | 0.6955 | 0.0138394
186294 | First Floor | Level : Second Floor | Second Floor | -0.102 | 9.77 | 0 | 12 | 8.346 | 0.6955 | 0.0138394
186120 | First Floor | Level : Second Floor | Second Floor | -0.102 | 9.77 | 0 | 12 | 8.346 | 0.6955 | 0.0138394
185452 | First Floor | Level : Second Floor | Second Floor | -0.102 | 8.57 | 0 | 10 | 7.146 | 0.7146 | 0.0120454
189638 | Second Floor | Level : Roof - Main | Roof - Main | 0 | 5.309 | 0 | 5 | 3.885 | 0.777 | 0.00717022
186250 | First Floor | Level : Second Floor | Second Floor | -0.102 | 6.629 | 0 | 7 | 5.205 | 0.743571 | 0.00914362
185493 | First Floor | Level : Second Floor | Second Floor | -0.102 | 10.039 | 0 | 12 | 8.615 | 0.717917 | 0.0142416
185958 | First Floor | Level : Second Floor | Second Floor | -0.102 | 9.769 | 0 | 12 | 8.345 | 0.695417 | 0.0138379
189728 | Second Floor | Level : Roof - Main | Roof - Main | 0 | 5.309 | 2.01996e-30 | 5 | 3.885 | 0.777 | 0.00717022
185737 | First Floor | Level : Second Floor | Second Floor | -0.102 | 10.039 | 0 | 12 | 8.615 | 0.717917 | 0.0142416
185653 | First Floor | Level : Second Floor | Second Floor | -0.102 | 5.309 | 0 | 5 | 3.885 | 0.777 | 0.00717022
186295 | First Floor | Level : Second Floor | Second Floor | -0.102 | 9.77 | 0 | 12 | 8.346 | 0.6955 | 0.0138394
186148 | First Floor | Level : Second Floor | Second Floor | -0.102 | 6.05 | 0 | 6 | 4.626 | 0.771 | 0.00827801
186283 | First Floor | Level : Second Floor | Second Floor | -0.102 | 6.629 | 0 | 7 | 5.205 | 0.743571 | 0.00914362
189656 | Second Floor | Level : Roof - Main | Roof - Main | 0 | 9.77 | 6.53056e-31 | 12 | 8.346 | 0.6955 | 0.0138394
189467 | Second Floor | Level : Roof - Main | Roof - Main | 0 | 8.57 | 0 | 10 | 7.146 | 0.7146 | 0.0120454
189379 | Second Floor | Level : Roof - Main | Roof - Main | 0 | 6.629 | 0 | 7 | 5.205 | 0.743571 | 0.00914362
189687 | Second Floor | Level : Roof - Main | Roof - Main | 0 | 9.769 | 9.79552e-31 | 12 | 8.345 | 0.695417 | 0.0138379
219987 | Second Floor | Level : Roof - Main | Roof - Main | 0 | 8.975 | 1.30141e-30 | 11 | 7.551 | 0.686455 | 0.0126509
220048 | Second Floor | Level : Roof - Main | Roof - Main | 0 | 8.975 | 1.30141e-30 | 11 | 7.551 | 0.686455 | 0.0126509
185741 | First Floor | Level : Second Floor | Second Floor | -0.102 | 10.039 | 0 | 12 | 8.615 | 0.717917 | 0.0142416
186262 | First Floor | Level : Second Floor | Second Floor | -0.102 | 9.77 | 6.53056e-31 | 12 | 8.346 | 0.6955 | 0.0138394
185758 | First Floor | Level : Second Floor | Second Floor | -0.102 | 10.039 | 0 | 12 | 8.615 | 0.717917 | 0.0142416
186132 | First Floor | Level : Second Floor | Second Floor | -0.102 | 5.309 | 0 | 5 | 3.885 | 0.777 | 0.00717022
185536 | First Floor | Level : Second Floor | Second Floor | -0.102 | 10.039 | 0 | 12 | 8.615 | 0.717917 | 0.0142416
190264 | Second Floor | Level : Roof - Main | Roof - Main | 0 | 8.57 | 1.97385e-30 | 10 | 7.146 | 0.7146 | 0.0120454
185933 | First Floor | Level : Second Floor | Second Floor | -0.102 | 9.77 | 0 | 12 | 8.346 | 0.6955 | 0.0138394
189688 | Second Floor | Level : Roof - Main | Roof - Main | 0 | 9.769 | 9.79552e-31 | 12 | 8.345 | 0.695417 | 0.0138379
186131 | First Floor | Level : Second Floor | Second Floor | -0.102 | 5.309 | 0 | 5 | 3.885 | 0.777 | 0.00717022
189952 | Second Floor | Level : Roof - Main | Roof - Main | 0 | 8.57 | 1.97385e-30 | 10 | 7.146 | 0.7146 | 0.0120454
189729 | Second Floor | Level : Roof - Main | Roof - Main | 0 | 5.309 | 2.01996e-30 | 5 | 3.885 | 0.777 | 0.00717022
189333 | Second Floor | Level : Roof - Main | Roof - Main | 0 | 9.77 | 0 | 12 | 8.346 | 0.6955 | 0.0138394
185959 | First Floor | Level : Second Floor | Second Floor | -0.102 | 9.769 | 0 | 12 | 8.345 | 0.695417 | 0.0138379
189382 | Second Floor | Level : Roof - Main | Roof - Main | 0 | 6.629 | 0 | 7 | 5.205 | 0.743571 | 0.00914362
188759 | First Floor | Level : Second Floor | Second Floor | -0.102 | 8.57 | 0 | 10 | 7.146 | 0.7146 | 0.0120454
189672 | Second Floor | Level : Roof - Main | Roof - Main | 0 | 6.629 | 0 | 7 | 5.205 | 0.743571 | 0.00914362
185365 | First Floor | Level : Second Floor | Second Floor | -0.102 | 5.309 | 0 | 5 | 3.885 | 0.777 | 0.00717022
189466 | Second Floor | Level : Roof - Main | Roof - Main | 0 | 8.57 | 0 | 10 | 7.146 | 0.7146 | 0.0120454
189674 | Second Floor | Level : Roof - Main | Roof - Main | 0 | 6.629 | 0 | 7 | 5.205 | 0.743571 | 0.00914362
185636 | First Floor | Level : Second Floor | Second Floor | -0.102 | 9.77 | 0 | 12 | 8.346 | 0.6955 | 0.0138394
189653 | Second Floor | Level : Roof - Main | Roof - Main | 0 | 9.77 | 6.53056e-31 | 12 | 8.346 | 0.6955 | 0.0138394
185771 | First Floor | Level : Second Floor | Second Floor | -0.102 | 10.039 | 0 | 12 | 8.615 | 0.717917 | 0.0142416
189309 | Second Floor | Level : Roof - Main | Roof - Main | 0 | 5.309 | 0 | 5 | 3.885 | 0.777 | 0.00717022
185667 | First Floor | Level : Second Floor | Second Floor | -0.102 | 8.57 | 0 | 10 | 7.146 | 0.7146 | 0.0120454
186081 | First Floor | Level : Second Floor | Second Floor | -0.102 | 9.77 | 0 | 12 | 8.346 | 0.6955 | 0.0138394
186282 | First Floor | Level : Second Floor | Second Floor | -0.102 | 6.629 | 0 | 7 | 5.205 | 0.743571 | 0.00914362
186264 | First Floor | Level : Second Floor | Second Floor | -0.102 | 9.77 | 6.53056e-31 | 12 | 8.346 | 0.6955 | 0.0138394
185670 | First Floor | Level : Second Floor | Second Floor | -0.102 | 8.57 | 0 | 10 | 7.146 | 0.7146 | 0.0120454
188805 | First Floor | Level : Second Floor | Second Floor | -0.102 | 5.697 | 1.31467e-30 | 6 | 4.273 | 0.712167 | 0.00775028
219951 | Second Floor | Level : Roof - Main | Roof - Main | 0 | 8.975 | 0 | 11 | 7.551 | 0.686455 | 0.0126509
188724 | First Floor | Level : Second Floor | Second Floor | -0.102 | 2.834 | 0 | 2 | 1.41 | 0.705 | 0.00347009
188806 | First Floor | Level : Second Floor | Second Floor | -0.102 | 5.697 | 1.31467e-30 | 6 | 4.273 | 0.712167 | 0.00775028
188819 | First Floor | Level : Second Floor | Second Floor | -0.102 | 8.57 | 1.97385e-30 | 10 | 7.146 | 0.7146 | 0.0120454
185630 | First Floor | Level : Second Floor | Second Floor | -0.102 | 9.77 | 0 | 12 | 8.346 | 0.6955 | 0.0138394
220002 | Second Floor | Level : Roof - Main | Roof - Main | 0 | 8.975 | 0 | 11 | 7.551 | 0.686455 | 0.0126509
189332 | Second Floor | Level : Roof - Main | Roof - Main | 0 | 9.77 | 0 | 12 | 8.346 | 0.6955 | 0.0138394
186280 | First Floor | Level : Second Floor | Second Floor | -0.102 | 6.629 | 0 | 7 | 5.205 | 0.743571 | 0.00914362
185606 | First Floor | Level : Second Floor | Second Floor | -0.102 | 6.05 | 0 | 6 | 4.626 | 0.771 | 0.00827801
185955 | First Floor | Level : Second Floor | Second Floor | -0.102 | 9.769 | 0 | 12 | 8.345 | 0.695417 | 0.0138379
189971 | Second Floor | Level : Roof - Main | Roof - Main | 0 | 8.57 | 0 | 10 | 7.146 | 0.7146 | 0.0120454
185704 | First Floor | Level : Second Floor | Second Floor | -0.102 | 8.57 | 0 | 10 | 7.146 | 0.7146 | 0.0120454
189704 | Second Floor | Level : Roof - Main | Roof - Main | 0 | 9.769 | 9.79552e-31 | 12 | 8.345 | 0.695417 | 0.0138379
185706 | First Floor | Level : Second Floor | Second Floor | -0.102 | 8.57 | 0 | 10 | 7.146 | 0.7146 | 0.0120454
189432 | Second Floor | Level : Roof - Main | Roof - Main | 0 | 8.57 | 0 | 10 | 7.146 | 0.7146 | 0.0120454
189311 | Second Floor | Level : Roof - Main | Roof - Main | 0 | 5.309 | 0 | 5 | 3.885 | 0.777 | 0.00717022
189604 | Second Floor | Level : Roof - Main | Roof - Main | 0 | 5.309 | 0 | 5 | 3.885 | 0.777 | 0.00717022
189381 | Second Floor | Level : Roof - Main | Roof - Main | 0 | 6.629 | 0 | 7 | 5.205 | 0.743571 | 0.00914362
186245 | First Floor | Level : Second Floor | Second Floor | -0.102 | 6.629 | 0 | 7 | 5.205 | 0.743571 | 0.00914362
189655 | Second Floor | Level : Roof - Main | Roof - Main | 0 | 9.77 | 6.53056e-31 | 12 | 8.346 | 0.6955 | 0.0138394
220046 | Second Floor | Level : Roof - Main | Roof - Main | 0 | 8.975 | 1.30141e-30 | 11 | 7.551 | 0.686455 | 0.0126509
185953 | First Floor | Level : Second Floor | Second Floor | -0.102 | 9.769 | 0 | 12 | 8.345 | 0.695417 | 0.0138379
185603 | First Floor | Level : Second Floor | Second Floor | -0.102 | 6.05 | 0 | 6 | 4.626 | 0.771 | 0.00827801
185954 | First Floor | Level : Second Floor | Second Floor | -0.102 | 9.769 | 0 | 12 | 8.345 | 0.695417 | 0.0138379
186297 | First Floor | Level : Second Floor | Second Floor | -0.102 | 9.77 | 0 | 12 | 8.346 | 0.6955 | 0.0138394
188390 | First Floor | Level : Second Floor | Second Floor | -0.102 | 7.402 | 0 | 8 | 5.978 | 0.74725 | 0.0102993
189336 | Second Floor | Level : Roof - Main | Roof - Main | 0 | 9.77 | 0 | 12 | 8.346 | 0.6955 | 0.0138394
189673 | Second Floor | Level : Roof - Main | Roof - Main | 0 | 6.629 | 0 | 7 | 5.205 | 0.743571 | 0.00914362
186134 | First Floor | Level : Second Floor | Second Floor | -0.102 | 5.309 | 0 | 5 | 3.885 | 0.777 | 0.00717022
188821 | First Floor | Level : Second Floor | Second Floor | -0.102 | 8.57 | 1.97385e-30 | 10 | 7.146 | 0.7146 | 0.0120454
185935 | First Floor | Level : Second Floor | Second Floor | -0.102 | 9.77 | 0 | 12 | 8.346 | 0.6955 | 0.0138394
219948 | Second Floor | Level : Roof - Main | Roof - Main | 0 | 8.975 | 0 | 11 | 7.551 | 0.686455 | 0.0126509
219989 | Second Floor | Level : Roof - Main | Roof - Main | 0 | 8.975 | 1.30141e-30 | 11 | 7.551 | 0.686455 | 0.0126509
186151 | First Floor | Level : Second Floor | Second Floor | -0.102 | 6.05 | 0 | 6 | 4.626 | 0.771 | 0.00827801
185754 | First Floor | Level : Second Floor | Second Floor | -0.102 | 10.039 | 0 | 12 | 8.615 | 0.717917 | 0.0142416
186016 | First Floor | Level : Second Floor | Second Floor | -0.102 | 9.77 | 0 | 12 | 8.346 | 0.6955 | 0.0138394
189310 | Second Floor | Level : Roof - Main | Roof - Main | 0 | 5.309 | 0 | 5 | 3.885 | 0.777 | 0.00717022
188760 | First Floor | Level : Second Floor | Second Floor | -0.102 | 8.57 | 0 | 10 | 7.146 | 0.7146 | 0.0120454
185574 | First Floor | Level : Second Floor | Second Floor | -0.102 | 9.77 | 0 | 12 | 8.346 | 0.6955 | 0.0138394
186068 | First Floor | Level : Second Floor | Second Floor | -0.102 | 5.309 | 0 | 5 | 3.885 | 0.777 | 0.00717022
189380 | Second Floor | Level : Roof - Main | Roof - Main | 0 | 6.629 | 0 | 7 | 5.205 | 0.743571 | 0.00914362
189587 | Second Floor | Level : Roof - Main | Roof - Main | 0 | 5.309 | 0 | 5 | 3.885 | 0.777 | 0.00717022
185650 | First Floor | Level : Second Floor | Second Floor | -0.102 | 5.309 | 0 | 5 | 3.885 | 0.777 | 0.00717022
186014 | First Floor | Level : Second Floor | Second Floor | -0.102 | 9.77 | 0 | 12 | 8.346 | 0.6955 | 0.0138394
189689 | Second Floor | Level : Roof - Main | Roof - Main | 0 | 9.769 | 9.79552e-31 | 12 | 8.345 | 0.695417 | 0.0138379
185721 | First Floor | Level : Second Floor | Second Floor | -0.102 | 9.77 | 0 | 12 | 8.346 | 0.6955 | 0.0138394
185956 | First Floor | Level : Second Floor | Second Floor | -0.102 | 9.769 | 0 | 12 | 8.345 | 0.695417 | 0.0138379
185753 | First Floor | Level : Second Floor | Second Floor | -0.102 | 10.039 | 0 | 12 | 8.615 | 0.717917 | 0.0142416
185671 | First Floor | Level : Second Floor | Second Floor | -0.102 | 8.57 | 0 | 10 | 7.146 | 0.7146 | 0.0120454
189334 | Second Floor | Level : Roof - Main | Roof - Main | 0 | 9.77 | 0 | 12 | 8.346 | 0.6955 | 0.0138394
219947 | Second Floor | Level : Roof - Main | Roof - Main | 0 | 8.975 | 0 | 11 | 7.551 | 0.686455 | 0.0126509
188820 | First Floor | Level : Second Floor | Second Floor | -0.102 | 8.57 | 1.97385e-30 | 10 | 7.146 | 0.7146 | 0.0120454
219945 | Second Floor | Level : Roof - Main | Roof - Main | 0 | 8.975 | 0 | 11 | 7.551 | 0.686455 | 0.0126509
186261 | First Floor | Level : Second Floor | Second Floor | -0.102 | 9.77 | 6.53056e-31 | 12 | 8.346 | 0.6955 | 0.0138394
186154 | First Floor | Level : Second Floor | Second Floor | -0.102 | 6.05 | 0 | 6 | 4.626 | 0.771 | 0.00827801
186153 | First Floor | Level : Second Floor | Second Floor | -0.102 | 6.05 | 0 | 6 | 4.626 | 0.771 | 0.00827801
189686 | Second Floor | Level : Roof - Main | Roof - Main | 0 | 9.769 | 9.79552e-31 | 12 | 8.345 | 0.695417 | 0.0138379
186300 | First Floor | Level : Second Floor | Second Floor | -0.102 | 9.77 | 0 | 12 | 8.346 | 0.6955 | 0.0138394
189685 | Second Floor | Level : Roof - Main | Roof - Main | 0 | 9.769 | 9.79552e-31 | 12 | 8.345 | 0.695417 | 0.0138379
189605 | Second Floor | Level : Roof - Main | Roof - Main | 0 | 5.309 | 0 | 5 | 3.885 | 0.777 | 0.00717022
185572 | First Floor | Level : Second Floor | Second Floor | -0.102 | 9.77 | 0 | 12 | 8.346 | 0.6955 | 0.0138394
185364 | First Floor | Level : Second Floor | Second Floor | -0.102 | 5.309 | 0 | 5 | 3.885 | 0.777 | 0.00717022
219949 | Second Floor | Level : Roof - Main | Roof - Main | 0 | 8.975 | 0 | 11 | 7.551 | 0.686455 | 0.0126509
186118 | First Floor | Level : Second Floor | Second Floor | -0.102 | 9.77 | 0 | 12 | 8.346 | 0.6955 | 0.0138394
188807 | First Floor | Level : Second Floor | Second Floor | -0.102 | 5.697 | 1.31467e-30 | 6 | 4.273 | 0.712167 | 0.00775028
185720 | First Floor | Level : Second Floor | Second Floor | -0.102 | 9.77 | 0 | 12 | 8.346 | 0.6955 | 0.0138394
185701 | First Floor | Level : Second Floor | Second Floor | -0.102 | 8.57 | 0 | 10 | 7.146 | 0.7146 | 0.0120454
189607 | Second Floor | Level : Roof - Main | Roof - Main | 0 | 5.309 | 0 | 5 | 3.885 | 0.777 | 0.00717022
219986 | Second Floor | Level : Roof - Main | Roof - Main | 0 | 8.975 | 1.30141e-30 | 11 | 7.551 | 0.686455 | 0.0126509
186149 | First Floor | Level : Second Floor | Second Floor | -0.102 | 6.05 | 0 | 6 | 4.626 | 0.771 | 0.00827801
186116 | First Floor | Level : Second Floor | Second Floor | -0.102 | 9.77 | 0 | 12 | 8.346 | 0.6955 | 0.0138394
186066 | First Floor | Level : Second Floor | Second Floor | -0.102 | 5.309 | 0 | 5 | 3.885 | 0.777 | 0.00717022
185703 | First Floor | Level : Second Floor | Second Floor | -0.102 | 8.57 | 0 | 10 | 7.146 | 0.7146 | 0.0120454
185770 | First Floor | Level : Second Floor | Second Floor | -0.102 | 10.039 | 0 | 12 | 8.615 | 0.717917 | 0.0142416
185684 | First Floor | Level : Second Floor | Second Floor | -0.102 | 8.57 | 0 | 10 | 7.146 | 0.7146 | 0.0120454
185755 | First Floor | Level : Second Floor | Second Floor | -0.102 | 10.039 | 0 | 12 | 8.615 | 0.717917 | 0.0142416
185651 | First Floor | Level : Second Floor | Second Floor | -0.102 | 5.309 | 0 | 5 | 3.885 | 0.777 | 0.00717022
189954 | Second Floor | Level : Roof - Main | Roof - Main | 0 | 8.57 | 1.97385e-30 | 10 | 7.146 | 0.7146 | 0.0120454
189052 | First Floor | Level : Second Floor | Second Floor | -0.102 | 6.629 | 0 | 7 | 5.205 | 0.743571 | 0.00914362
186115 | First Floor | Level : Second Floor | Second Floor | -0.102 | 9.77 | 0 | 12 | 8.346 | 0.6955 | 0.0138394
186296 | First Floor | Level : Second Floor | Second Floor | -0.102 | 9.77 | 0 | 12 | 8.346 | 0.6955 | 0.0138394
186136 | First Floor | Level : Second Floor | Second Floor | -0.102 | 5.309 | 0 | 5 | 3.885 | 0.777 | 0.00717022
220005 | Second Floor | Level : Roof - Main | Roof - Main | 0 | 8.975 | 0 | 11 | 7.551 | 0.686455 | 0.0126509
185652 | First Floor | Level : Second Floor | Second Floor | -0.102 | 5.309 | 0 | 5 | 3.885 | 0.777 | 0.00717022
185901 | First Floor | Level : Second Floor | Second Floor | -0.102 | 9.77 | 0 | 12 | 8.346 | 0.6955 | 0.0138394
186133 | First Floor | Level : Second Floor | Second Floor | -0.102 | 5.309 | 0 | 5 | 3.885 | 0.777 | 0.00717022
185723 | First Floor | Level : Second Floor | Second Floor | -0.102 | 9.77 | 0 | 12 | 8.346 | 0.6955 | 0.0138394
189591 | Second Floor | Level : Roof - Main | Roof - Main | 0 | 5.309 | 0 | 5 | 3.885 | 0.777 | 0.00717022
185569 | First Floor | Level : Second Floor | Second Floor | -0.102 | 9.77 | 0 | 12 | 8.346 | 0.6955 | 0.0138394
185757 | First Floor | Level : Second Floor | Second Floor | -0.102 | 10.039 | 0 | 12 | 8.615 | 0.717917 | 0.0142416
185932 | First Floor | Level : Second Floor | Second Floor | -0.102 | 9.77 | 0 | 12 | 8.346 | 0.6955 | 0.0138394
185895 | First Floor | Level : Second Floor | Second Floor | -0.102 | 9.77 | 0 | 12 | 8.346 | 0.6955 | 0.0138394
186152 | First Floor | Level : Second Floor | Second Floor | -0.102 | 6.05 | 0 | 6 | 4.626 | 0.771 | 0.00827801
185957 | First Floor | Level : Second Floor | Second Floor | -0.102 | 9.769 | 0 | 12 | 8.345 | 0.695417 | 0.0138379
186150 | First Floor | Level : Second Floor | Second Floor | -0.102 | 6.05 | 0 | 6 | 4.626 | 0.771 | 0.00827801
185588 | First Floor | Level : Second Floor | Second Floor | -0.102 | 5.309 | 0 | 5 | 3.885 | 0.777 | 0.00717022
185656 | First Floor | Level : Second Floor | Second Floor | -0.102 | 5.309 | 0 | 5 | 3.885 | 0.777 | 0.00717022
186082 | First Floor | Level : Second Floor | Second Floor | -0.102 | 9.77 | 0 | 12 | 8.346 | 0.6955 | 0.0138394
185605 | First Floor | Level : Second Floor | Second Floor | -0.102 | 6.05 | 0 | 6 | 4.626 | 0.771 | 0.00827801
186248 | First Floor | Level : Second Floor | Second Floor | -0.102 | 6.629 | 0 | 7 | 5.205 | 0.743571 | 0.00914362
185687 | First Floor | Level : Second Floor | Second Floor | -0.102 | 8.57 | 0 | 10 | 7.146 | 0.7146 | 0.0120454
186119 | First Floor | Level : Second Floor | Second Floor | -0.102 | 9.77 | 0 | 12 | 8.346 | 0.6955 | 0.0138394
185635 | First Floor | Level : Second Floor | Second Floor | -0.102 | 9.77 | 0 | 12 | 8.346 | 0.6955 | 0.0138394
185618 | First Floor | Level : Second Floor | Second Floor | -0.102 | 6.05 | 0 | 6 | 4.626 | 0.771 | 0.00827801
186063 | First Floor | Level : Second Floor | Second Floor | -0.102 | 5.309 | 0 | 5 | 3.885 | 0.777 | 0.00717022
185672 | First Floor | Level : Second Floor | Second Floor | -0.102 | 8.57 | 0 | 10 | 7.146 | 0.7146 | 0.0120454
185934 | First Floor | Level : Second Floor | Second Floor | -0.102 | 9.77 | 0 | 12 | 8.346 | 0.6955 | 0.0138394
185585 | First Floor | Level : Second Floor | Second Floor | -0.102 | 5.309 | 0 | 5 | 3.885 | 0.777 | 0.00717022
189307 | Second Floor | Level : Roof - Main | Roof - Main | 0 | 5.309 | 0 | 5 | 3.885 | 0.777 | 0.00717022
185688 | First Floor | Level : Second Floor | Second Floor | -0.102 | 8.57 | 0 | 10 | 7.146 | 0.7146 | 0.0120454
189703 | Second Floor | Level : Roof - Main | Roof - Main | 0 | 9.769 | 9.79552e-31 | 12 | 8.345 | 0.695417 | 0.0138379
185936 | First Floor | Level : Second Floor | Second Floor | -0.102 | 9.77 | 0 | 12 | 8.346 | 0.6955 | 0.0138394
186137 | First Floor | Level : Second Floor | Second Floor | -0.102 | 5.309 | 0 | 5 | 3.885 | 0.777 | 0.00717022
185829 | First Floor | Level : Second Floor | Second Floor | -0.102 | 9.77 | 0 | 12 | 8.346 | 0.6955 | 0.0138394
185724 | First Floor | Level : Second Floor | Second Floor | -0.102 | 9.77 | 0 | 12 | 8.346 | 0.6955 | 0.0138394
186249 | First Floor | Level : Second Floor | Second Floor | -0.102 | 6.629 | 0 | 7 | 5.205 | 0.743571 | 0.00914362
189589 | Second Floor | Level : Roof - Main | Roof - Main | 0 | 5.309 | 0 | 5 | 3.885 | 0.777 | 0.00717022
189377 | Second Floor | Level : Roof - Main | Roof - Main | 0 | 6.629 | 0 | 7 | 5.205 | 0.743571 | 0.00914362
185602 | First Floor | Level : Second Floor | Second Floor | -0.102 | 6.05 | 0 | 6 | 4.626 | 0.771 | 0.00827801
185654 | First Floor | Level : Second Floor | Second Floor | -0.102 | 5.309 | 0 | 5 | 3.885 | 0.777 | 0.00717022
188822 | First Floor | Level : Second Floor | Second Floor | -0.102 | 8.57 | 1.97385e-30 | 10 | 7.146 | 0.7146 | 0.0120454
185705 | First Floor | Level : Second Floor | Second Floor | -0.102 | 8.57 | 0 | 10 | 7.146 | 0.7146 | 0.0120454
186018 | First Floor | Level : Second Floor | Second Floor | -0.102 | 9.77 | 0 | 12 | 8.346 | 0.6955 | 0.0138394
186017 | First Floor | Level : Second Floor | Second Floor | -0.102 | 9.77 | 0 | 12 | 8.346 | 0.6955 | 0.0138394
185633 | First Floor | Level : Second Floor | Second Floor | -0.102 | 9.77 | 0 | 12 | 8.346 | 0.6955 | 0.0138394
185931 | First Floor | Level : Second Floor | Second Floor | -0.102 | 9.77 | 0 | 12 | 8.346 | 0.6955 | 0.0138394
186052 | First Floor | Level : Second Floor | Second Floor | -0.102 | 5.309 | 0 | 5 | 3.885 | 0.777 | 0.00717022
186067 | First Floor | Level : Second Floor | Second Floor | -0.102 | 5.309 | 0 | 5 | 3.885 | 0.777 | 0.00717022
185707 | First Floor | Level : Second Floor | Second Floor | -0.102 | 8.57 | 0 | 10 | 7.146 | 0.7146 | 0.0120454
185702 | First Floor | Level : Second Floor | Second Floor | -0.102 | 8.57 | 0 | 10 | 7.146 | 0.7146 | 0.0120454
220004 | Second Floor | Level : Roof - Main | Roof - Main | 0 | 8.975 | 0 | 11 | 7.551 | 0.686455 | 0.0126509
189603 | Second Floor | Level : Roof - Main | Roof - Main | 0 | 5.309 | 0 | 5 | 3.885 | 0.777 | 0.00717022
189592 | Second Floor | Level : Roof - Main | Roof - Main | 0 | 5.309 | 0 | 5 | 3.885 | 0.777 | 0.00717022
186015 | First Floor | Level : Second Floor | Second Floor | -0.102 | 9.77 | 0 | 12 | 8.346 | 0.6955 | 0.0138394
186247 | First Floor | Level : Second Floor | Second Floor | -0.102 | 6.629 | 0 | 7 | 5.205 | 0.743571 | 0.00914362
185604 | First Floor | Level : Second Floor | Second Floor | -0.102 | 6.05 | 0 | 6 | 4.626 | 0.771 | 0.00827801
189259 | First Floor | Level : Second Floor | Second Floor | -0.102 | 6.05 | 0 | 6 | 4.626 | 0.771 | 0.00827801
186246 | First Floor | Level : Second Floor | Second Floor | -0.102 | 6.629 | 0 | 7 | 5.205 | 0.743571 | 0.00914362
185573 | First Floor | Level : Second Floor | Second Floor | -0.102 | 9.77 | 0 | 12 | 8.346 | 0.6955 | 0.0138394
186065 | First Floor | Level : Second Floor | Second Floor | -0.102 | 5.309 | 0 | 5 | 3.885 | 0.777 | 0.00717022
185601 | First Floor | Level : Second Floor | Second Floor | -0.102 | 6.05 | 0 | 6 | 4.626 | 0.771 | 0.00827801
185586 | First Floor | Level : Second Floor | Second Floor | -0.102 | 5.309 | 0 | 5 | 3.885 | 0.777 | 0.00717022
186086 | First Floor | Level : Second Floor | Second Floor | -0.102 | 9.77 | 0 | 12 | 8.346 | 0.6955 | 0.0138394
186114 | First Floor | Level : Second Floor | Second Floor | -0.102 | 9.77 | 0 | 12 | 8.346 | 0.6955 | 0.0138394
185655 | First Floor | Level : Second Floor | Second Floor | -0.102 | 5.309 | 0 | 5 | 3.885 | 0.777 | 0.00717022
186020 | First Floor | Level : Second Floor | Second Floor | -0.102 | 9.77 | 0 | 12 | 8.346 | 0.6955 | 0.0138394
220003 | Second Floor | Level : Roof - Main | Roof - Main | 0 | 8.975 | 0 | 11 | 7.551 | 0.686455 | 0.0126509
186117 | First Floor | Level : Second Floor | Second Floor | -0.102 | 9.77 | 0 | 12 | 8.346 | 0.6955 | 0.0138394
185589 | First Floor | Level : Second Floor | Second Floor | -0.102 | 5.309 | 0 | 5 | 3.885 | 0.777 | 0.00717022
185689 | First Floor | Level : Second Floor | Second Floor | -0.102 | 8.57 | 0 | 10 | 7.146 | 0.7146 | 0.0120454
185634 | First Floor | Level : Second Floor | Second Floor | -0.102 | 9.77 | 0 | 12 | 8.346 | 0.6955 | 0.0138394
185828 | First Floor | Level : Second Floor | Second Floor | -0.102 | 9.77 | 0 | 12 | 8.346 | 0.6955 | 0.0138394
185900 | First Floor | Level : Second Floor | Second Floor | -0.102 | 9.77 | 0 | 12 | 8.346 | 0.6955 | 0.0138394
185898 | First Floor | Level : Second Floor | Second Floor | -0.102 | 9.77 | 0 | 12 | 8.346 | 0.6955 | 0.0138394
185587 | First Floor | Level : Second Floor | Second Floor | -0.102 | 5.309 | 0 | 5 | 3.885 | 0.777 | 0.00717022
185685 | First Floor | Level : Second Floor | Second Floor | -0.102 | 8.57 | 0 | 10 | 7.146 | 0.7146 | 0.0120454
186064 | First Floor | Level : Second Floor | Second Floor | -0.102 | 5.309 | 0 | 5 | 3.885 | 0.777 | 0.00717022
186035 | First Floor | Level : Second Floor | Second Floor | -0.102 | 5.309 | 0 | 5 | 3.885 | 0.777 | 0.00717022
189588 | Second Floor | Level : Roof - Main | Roof - Main | 0 | 5.309 | 0 | 5 | 3.885 | 0.777 | 0.00717022
185673 | First Floor | Level : Second Floor | Second Floor | -0.102 | 8.57 | 0 | 10 | 7.146 | 0.7146 | 0.0120454
185826 | First Floor | Level : Second Floor | Second Floor | -0.102 | 9.77 | 0 | 12 | 8.346 | 0.6955 | 0.0138394
186135 | First Floor | Level : Second Floor | Second Floor | -0.102 | 5.309 | 0 | 5 | 3.885 | 0.777 | 0.00717022
186036 | First Floor | Level : Second Floor | Second Floor | -0.102 | 5.309 | 0 | 5 | 3.885 | 0.777 | 0.00717022
185825 | First Floor | Level : Second Floor | Second Floor | -0.102 | 9.77 | 0 | 12 | 8.346 | 0.6955 | 0.0138394
185897 | First Floor | Level : Second Floor | Second Floor | -0.102 | 9.77 | 0 | 12 | 8.346 | 0.6955 | 0.0138394
185570 | First Floor | Level : Second Floor | Second Floor | -0.102 | 9.77 | 0 | 12 | 8.346 | 0.6955 | 0.0138394
185686 | First Floor | Level : Second Floor | Second Floor | -0.102 | 8.57 | 0 | 10 | 7.146 | 0.7146 | 0.0120454
189308 | Second Floor | Level : Roof - Main | Roof - Main | 0 | 5.309 | 0 | 5 | 3.885 | 0.777 | 0.00717022
186034 | First Floor | Level : Second Floor | Second Floor | -0.102 | 5.309 | 0 | 5 | 3.885 | 0.777 | 0.00717022
186084 | First Floor | Level : Second Floor | Second Floor | -0.102 | 9.77 | 0 | 12 | 8.346 | 0.6955 | 0.0138394
189378 | Second Floor | Level : Roof - Main | Roof - Main | 0 | 6.629 | 0 | 7 | 5.205 | 0.743571 | 0.00914362
186032 | First Floor | Level : Second Floor | Second Floor | -0.102 | 5.309 | 0 | 5 | 3.885 | 0.777 | 0.00717022
186083 | First Floor | Level : Second Floor | Second Floor | -0.102 | 9.77 | 0 | 12 | 8.346 | 0.6955 | 0.0138394
185571 | First Floor | Level : Second Floor | Second Floor | -0.102 | 9.77 | 0 | 12 | 8.346 | 0.6955 | 0.0138394
186048 | First Floor | Level : Second Floor | Second Floor | -0.102 | 5.309 | 0 | 5 | 3.885 | 0.777 | 0.00717022
186031 | First Floor | Level : Second Floor | Second Floor | -0.102 | 5.309 | 0 | 5 | 3.885 | 0.777 | 0.00717022
185896 | First Floor | Level : Second Floor | Second Floor | -0.102 | 9.77 | 0 | 12 | 8.346 | 0.6955 | 0.0138394
186085 | First Floor | Level : Second Floor | Second Floor | -0.102 | 9.77 | 0 | 12 | 8.346 | 0.6955 | 0.0138394
185590 | First Floor | Level : Second Floor | Second Floor | -0.102 | 5.309 | 0 | 5 | 3.885 | 0.777 | 0.00717022
186019 | First Floor | Level : Second Floor | Second Floor | -0.102 | 9.77 | 0 | 12 | 8.346 | 0.6955 | 0.0138394
185899 | First Floor | Level : Second Floor | Second Floor | -0.102 | 9.77 | 0 | 12 | 8.346 | 0.6955 | 0.0138394
186037 | First Floor | Level : Second Floor | Second Floor | -0.102 | 5.309 | 0 | 5 | 3.885 | 0.777 | 0.00717022
185827 | First Floor | Level : Second Floor | Second Floor | -0.102 | 9.77 | 0 | 12 | 8.346 | 0.6955 | 0.0138394
186033 | First Floor | Level : Second Floor | Second Floor | -0.102 | 5.309 | 0 | 5 | 3.885 | 0.777 | 0.00717022
186051 | First Floor | Level : Second Floor | Second Floor | -0.102 | 5.309 | 0 | 5 | 3.885 | 0.777 | 0.00717022
186049 | First Floor | Level : Second Floor | Second Floor | -0.102 | 5.309 | 0 | 5 | 3.885 | 0.777 | 0.00717022
186050 | First Floor | Level : Second Floor | Second Floor | -0.102 | 5.309 | 0 | 5 | 3.885 | 0.777 | 0.00717022

# IfcBeam: M_W-Wide Flange:W460X60:176883 (277)
Material: Metal - Steel - 345 MPa
PSet_Revit_Constraints - z-Direction Justification: 0; z-Direction Offset Value: 0 m; Lateral Justification: 0; Cross-Section Rotation: 0 deg
PSet_Revit_Phasing - Phase Created: New Construction
PSet_Revit_Analytical Model - Rigid Links: 0; Horizontal Projection: Default
PSet_Revit_Materials and Finishes - Beam Material: Metal - Steel - 345 MPa
PSet_Revit_Other - InstallationDate: InstallationDate; SerialNumber: SerialNumber; WarrantyStartDate: WarrantyStartDate; BarCode: BarCode; AssetIdentifier: AssetIdentifier; TagNumber: TagNumber
PSet_Revit_Structural Analysis - Start Release: 3; Start Fx: no; Start Fy: no; Start Fz: no; Start Mx: no; Start My: yes; Start Mz: yes; End Release: 1; End Fx: no; End Fy: no; End Fz: no; End Mx: yes; End My: yes; End Mz: yes; Analyze As: 1
Pset_BeamCommon - Reference: M_W-Wide Flange:W460X60; IsExternal: no; LoadBearing: yes
PSet_Revit_Structural - Stick Symbol Location: 0
PSet_Revit_Type_Identity Data - Manufacturer: Manufacturer; OmniClass Number: 23.25.30.11.14.14; OmniClass Title: Beams
PSet_Revit_Type_Dimensions - bf: 0.153 m; d: 0.455 m; k: 0.031 m; kr: 0.0177 m; tf: 0.0133 m; tw: 0.008 m
